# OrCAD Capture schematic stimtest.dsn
size A

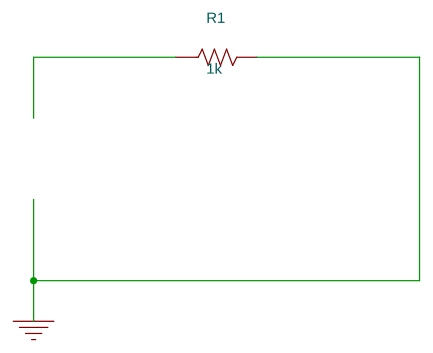
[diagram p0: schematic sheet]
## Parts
R1  1k  [AX/RC05]

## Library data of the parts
R1 = R

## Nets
0: R1.2

Not connected (* = marked no-connect by the designer): R1 1
